VERSION 5.8 ;
BUSBITCHARS "[]" ;
DIVIDERCHAR "/" ;

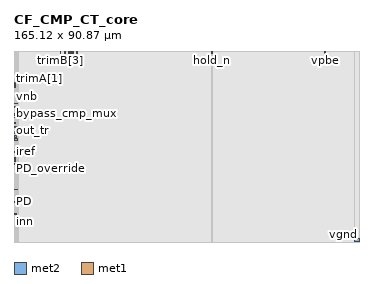
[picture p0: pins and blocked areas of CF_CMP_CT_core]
MACRO CF_CMP_CT_core
  CLASS BLOCK ;
  ORIGIN 0 0 ;
  FOREIGN CF_CMP_CT_core 0 0 ;
  SIZE 165.12 BY 90.87 ;
  PIN trimA[2]
    DIRECTION INPUT ;
    USE SIGNAL ;
    PORT
      LAYER met2 ;
        RECT 0 74.01 0.775 74.33 ;
    END
  END trimA[2]
  PIN trimA[1]
    DIRECTION INPUT ;
    USE SIGNAL ;
    PORT
      LAYER met2 ;
        RECT 0 74.49 0.77 74.81 ;
    END
  END trimA[1]
  PIN bypass_cmp_mux
    DIRECTION INPUT ;
    USE SIGNAL ;
    PORT
      LAYER met2 ;
        RECT 0 61.22 0.645 61.54 ;
    END
  END bypass_cmp_mux
  PIN trimB[4]
    DIRECTION INPUT ;
    USE SIGNAL ;
    PORT
      LAYER met1 ;
        RECT 27.305 90.115 27.625 90.87 ;
    END
  END trimB[4]
  PIN trimB[0]
    DIRECTION INPUT ;
    USE SIGNAL ;
    PORT
      LAYER met1 ;
        RECT 26.58 90.115 26.9 90.87 ;
    END
  END trimB[0]
  PIN trimB[1]
    DIRECTION INPUT ;
    USE SIGNAL ;
    PORT
      LAYER met1 ;
        RECT 26.02 90.175 26.335 90.87 ;
    END
  END trimB[1]
  PIN trimB[2]
    DIRECTION INPUT ;
    USE SIGNAL ;
    PORT
      LAYER met1 ;
        RECT 24.14 90.135 24.46 90.87 ;
    END
  END trimB[2]
  PIN trimB[3]
    DIRECTION INPUT ;
    USE SIGNAL ;
    PORT
      LAYER met1 ;
        RECT 22.135 90.245 22.455 90.87 ;
    END
  END trimB[3]
  PIN trimA[4]
    DIRECTION INPUT ;
    USE SIGNAL ;
    PORT
      LAYER met2 ;
        RECT 0 75.945 0.8 76.265 ;
    END
  END trimA[4]
  PIN trimA[3]
    DIRECTION INPUT ;
    USE SIGNAL ;
    PORT
      LAYER met2 ;
        RECT 0 75.45 0.805 75.77 ;
    END
  END trimA[3]
  PIN inn
    DIRECTION INPUT ;
    USE SIGNAL ;
    PORT
      LAYER met2 ;
        RECT 0 13.205 1.345 13.525 ;
    END
  END inn
  PIN vpb_ka
    DIRECTION INPUT ;
    USE SIGNAL ;
    PORT
      LAYER met2 ;
        RECT 0 48.565 1.555 49.265 ;
    END
  END vpb_ka
  PIN en
    DIRECTION INPUT ;
    USE SIGNAL ;
    PORT
      LAYER met2 ;
        RECT 0 54.985 1.58 55.305 ;
    END
  END en
  PIN iref
    DIRECTION INPUT ;
    USE SIGNAL ;
    PORT
      LAYER met2 ;
        RECT 0 42.935 0.82 43.245 ;
    END
  END iref
  PIN vpwr
    DIRECTION INPUT ;
    USE POWER ;
    PORT
      LAYER met2 ;
        RECT 0 60.32 1.78 61.05 ;
    END
  END vpwr
  PIN vpb
    DIRECTION INPUT ;
    USE POWER ;
    PORT
      LAYER met2 ;
        RECT 0 64.495 0.685 64.815 ;
    END
  END vpb
  PIN vnb
    DIRECTION INPUT ;
    USE GROUND ;
    PORT
      LAYER met2 ;
        RECT 1.71 69.605 2.39 69.925 ;
    END
  END vnb
  PIN vgnd
    DIRECTION INPUT ;
    USE GROUND ;
    PORT
      LAYER met2 ;
        RECT 162.9 0.27 165.06 1.805 ;
    END
  END vgnd
  PIN out
    DIRECTION OUTPUT ;
    USE SIGNAL ;
    PORT
      LAYER met2 ;
        RECT 0 66.085 1.76 66.37 ;
    END
  END out
  PIN out_tr
    DIRECTION OUTPUT ;
    USE SIGNAL ;
    PORT
      LAYER met2 ;
        RECT 0 56.88 0.935 57.2 ;
    END
  END out_tr
  PIN vpwr_ka
    DIRECTION INPUT ;
    USE SIGNAL ;
    PORT
      LAYER met2 ;
        RECT 0 50.005 1.245 50.705 ;
    END
  END vpwr_ka
  PIN cal_en
    DIRECTION INPUT ;
    USE SIGNAL ;
    PORT
      LAYER met2 ;
        RECT 0 59.315 1.465 59.635 ;
    END
  END cal_en
  PIN hyst
    DIRECTION INPUT ;
    USE SIGNAL ;
    PORT
      LAYER met2 ;
        RECT 0 51.74 1.12 52.06 ;
    END
  END hyst
  PIN PD
    DIRECTION INPUT ;
    USE SIGNAL ;
    PORT
      LAYER met2 ;
        RECT 0 19.105 1.02 19.425 ;
    END
  END PD
  PIN filt
    DIRECTION INPUT ;
    USE SIGNAL ;
    PORT
      LAYER met2 ;
        RECT 0 52.33 1.215 52.65 ;
    END
  END filt
  PIN PD_override
    DIRECTION INPUT ;
    USE SIGNAL ;
    PORT
      LAYER met2 ;
        RECT 0 38.685 0.945 39.005 ;
    END
  END PD_override
  PIN hold_n
    DIRECTION INPUT ;
    USE SIGNAL ;
    PORT
      LAYER met2 ;
        RECT 94.55 90.145 94.87 90.87 ;
    END
  END hold_n
  PIN enable_hv
    DIRECTION INPUT ;
    USE SIGNAL ;
    PORT
      LAYER met2 ;
        RECT 0 37.28 0.97 37.595 ;
    END
  END enable_hv
  PIN trimA[0]
    DIRECTION INPUT ;
    USE SIGNAL ;
    PORT
      LAYER met2 ;
        RECT 0 74.97 0.79 75.29 ;
    END
  END trimA[0]
  PIN vpbe
    DIRECTION INPUT ;
    USE POWER ;
    PORT
      LAYER met1 ;
        RECT 148.5 90.13 149.08 90.87 ;
    END
  END vpbe
  PIN vpwre
    DIRECTION INPUT ;
    USE POWER ;
    PORT
      LAYER met1 ;
        RECT 0 39.23 0.94 40.21 ;
    END
  END vpwre
  PIN sel1
    DIRECTION INPUT ;
    USE SIGNAL ;
    PORT
      LAYER met1 ;
        RECT 30.035 90.15 30.355 90.87 ;
    END
  END sel1
  PIN sel0
    DIRECTION INPUT ;
    USE SIGNAL ;
    PORT
      LAYER met1 ;
        RECT 28.15 90.125 28.47 90.87 ;
    END
  END sel0
  PIN inp
    DIRECTION INPUT ;
    USE SIGNAL ;
    PORT
      LAYER met1 ;
        RECT 0 24.89 1.645 25.21 ;
    END
  END inp
  OBS
    LAYER li1 ;
      RECT 0 0 165.12 90.87 ;
    LAYER met1 ;
      RECT 0 0 0.94 24.89 ;
      RECT 0 25.21 0.94 39.23 ;
      RECT 0 40.21 0.94 90.87 ;
      RECT 0.94 0 1.645 24.89 ;
      RECT 0.94 25.21 1.645 90.87 ;
      RECT 1.645 0 22.135 90.87 ;
      RECT 22.135 0 22.455 90.245 ;
      RECT 22.455 0 24.14 90.87 ;
      RECT 24.14 0 24.46 90.135 ;
      RECT 24.46 0 26.02 90.87 ;
      RECT 26.02 0 26.335 90.175 ;
      RECT 26.335 0 26.58 90.87 ;
      RECT 26.58 0 26.9 90.115 ;
      RECT 26.9 0 27.305 90.87 ;
      RECT 27.305 0 27.625 90.115 ;
      RECT 27.625 0 28.15 90.87 ;
      RECT 28.15 0 28.47 90.125 ;
      RECT 28.47 0 30.035 90.87 ;
      RECT 30.035 0 30.355 90.15 ;
      RECT 30.355 0 148.5 90.87 ;
      RECT 148.5 0 149.08 90.13 ;
      RECT 149.08 0 165.12 90.87 ;
    LAYER met2 ;
      RECT 0 0 0.645 13.205 ;
      RECT 0 13.525 0.645 19.105 ;
      RECT 0 19.425 0.645 37.28 ;
      RECT 0 37.595 0.645 38.685 ;
      RECT 0 39.005 0.645 42.935 ;
      RECT 0 43.245 0.645 48.565 ;
      RECT 0 49.265 0.645 50.005 ;
      RECT 0 50.705 0.645 51.74 ;
      RECT 0 52.06 0.645 52.33 ;
      RECT 0 52.65 0.645 54.985 ;
      RECT 0 55.305 0.645 56.88 ;
      RECT 0 57.2 0.645 59.315 ;
      RECT 0 59.635 0.645 60.32 ;
      RECT 0 61.05 0.645 61.22 ;
      RECT 0 61.54 0.645 64.495 ;
      RECT 0 64.815 0.645 66.085 ;
      RECT 0 66.37 0.645 74.01 ;
      RECT 0 74.33 0.645 74.49 ;
      RECT 0 74.81 0.645 74.97 ;
      RECT 0 75.29 0.645 75.45 ;
      RECT 0 75.77 0.645 75.945 ;
      RECT 0 76.265 0.645 90.87 ;
      RECT 0.645 0 0.685 13.205 ;
      RECT 0.645 13.525 0.685 19.105 ;
      RECT 0.645 19.425 0.685 37.28 ;
      RECT 0.645 37.595 0.685 38.685 ;
      RECT 0.645 39.005 0.685 42.935 ;
      RECT 0.645 43.245 0.685 48.565 ;
      RECT 0.645 49.265 0.685 50.005 ;
      RECT 0.645 50.705 0.685 51.74 ;
      RECT 0.645 52.06 0.685 52.33 ;
      RECT 0.645 52.65 0.685 54.985 ;
      RECT 0.645 55.305 0.685 56.88 ;
      RECT 0.645 57.2 0.685 59.315 ;
      RECT 0.645 59.635 0.685 60.32 ;
      RECT 0.645 61.05 0.685 64.495 ;
      RECT 0.645 64.815 0.685 66.085 ;
      RECT 0.645 66.37 0.685 74.01 ;
      RECT 0.645 74.33 0.685 74.49 ;
      RECT 0.645 74.81 0.685 74.97 ;
      RECT 0.645 75.29 0.685 75.45 ;
      RECT 0.645 75.77 0.685 75.945 ;
      RECT 0.645 76.265 0.685 90.87 ;
      RECT 0.685 0 0.77 13.205 ;
      RECT 0.685 13.525 0.77 19.105 ;
      RECT 0.685 19.425 0.77 37.28 ;
      RECT 0.685 37.595 0.77 38.685 ;
      RECT 0.685 39.005 0.77 42.935 ;
      RECT 0.685 43.245 0.77 48.565 ;
      RECT 0.685 49.265 0.77 50.005 ;
      RECT 0.685 50.705 0.77 51.74 ;
      RECT 0.685 52.06 0.77 52.33 ;
      RECT 0.685 52.65 0.77 54.985 ;
      RECT 0.685 55.305 0.77 56.88 ;
      RECT 0.685 57.2 0.77 59.315 ;
      RECT 0.685 59.635 0.77 60.32 ;
      RECT 0.685 61.05 0.77 66.085 ;
      RECT 0.685 66.37 0.77 74.01 ;
      RECT 0.685 74.33 0.77 74.49 ;
      RECT 0.685 74.81 0.77 74.97 ;
      RECT 0.685 75.29 0.77 75.45 ;
      RECT 0.685 75.77 0.77 75.945 ;
      RECT 0.685 76.265 0.77 90.87 ;
      RECT 0.77 0 0.775 13.205 ;
      RECT 0.77 13.525 0.775 19.105 ;
      RECT 0.77 19.425 0.775 37.28 ;
      RECT 0.77 37.595 0.775 38.685 ;
      RECT 0.77 39.005 0.775 42.935 ;
      RECT 0.77 43.245 0.775 48.565 ;
      RECT 0.77 49.265 0.775 50.005 ;
      RECT 0.77 50.705 0.775 51.74 ;
      RECT 0.77 52.06 0.775 52.33 ;
      RECT 0.77 52.65 0.775 54.985 ;
      RECT 0.77 55.305 0.775 56.88 ;
      RECT 0.77 57.2 0.775 59.315 ;
      RECT 0.77 59.635 0.775 60.32 ;
      RECT 0.77 61.05 0.775 66.085 ;
      RECT 0.77 66.37 0.775 74.01 ;
      RECT 0.77 74.33 0.775 74.97 ;
      RECT 0.77 75.29 0.775 75.45 ;
      RECT 0.77 75.77 0.775 75.945 ;
      RECT 0.77 76.265 0.775 90.87 ;
      RECT 0.775 0 0.79 13.205 ;
      RECT 0.775 13.525 0.79 19.105 ;
      RECT 0.775 19.425 0.79 37.28 ;
      RECT 0.775 37.595 0.79 38.685 ;
      RECT 0.775 39.005 0.79 42.935 ;
      RECT 0.775 43.245 0.79 48.565 ;
      RECT 0.775 49.265 0.79 50.005 ;
      RECT 0.775 50.705 0.79 51.74 ;
      RECT 0.775 52.06 0.79 52.33 ;
      RECT 0.775 52.65 0.79 54.985 ;
      RECT 0.775 55.305 0.79 56.88 ;
      RECT 0.775 57.2 0.79 59.315 ;
      RECT 0.775 59.635 0.79 60.32 ;
      RECT 0.775 61.05 0.79 66.085 ;
      RECT 0.775 66.37 0.79 74.97 ;
      RECT 0.775 75.29 0.79 75.45 ;
      RECT 0.775 75.77 0.79 75.945 ;
      RECT 0.775 76.265 0.79 90.87 ;
      RECT 0.79 0 0.8 13.205 ;
      RECT 0.79 13.525 0.8 19.105 ;
      RECT 0.79 19.425 0.8 37.28 ;
      RECT 0.79 37.595 0.8 38.685 ;
      RECT 0.79 39.005 0.8 42.935 ;
      RECT 0.79 43.245 0.8 48.565 ;
      RECT 0.79 49.265 0.8 50.005 ;
      RECT 0.79 50.705 0.8 51.74 ;
      RECT 0.79 52.06 0.8 52.33 ;
      RECT 0.79 52.65 0.8 54.985 ;
      RECT 0.79 55.305 0.8 56.88 ;
      RECT 0.79 57.2 0.8 59.315 ;
      RECT 0.79 59.635 0.8 60.32 ;
      RECT 0.79 61.05 0.8 66.085 ;
      RECT 0.79 66.37 0.8 75.45 ;
      RECT 0.79 75.77 0.8 75.945 ;
      RECT 0.79 76.265 0.8 90.87 ;
      RECT 0.8 0 0.805 13.205 ;
      RECT 0.8 13.525 0.805 19.105 ;
      RECT 0.8 19.425 0.805 37.28 ;
      RECT 0.8 37.595 0.805 38.685 ;
      RECT 0.8 39.005 0.805 42.935 ;
      RECT 0.8 43.245 0.805 48.565 ;
      RECT 0.8 49.265 0.805 50.005 ;
      RECT 0.8 50.705 0.805 51.74 ;
      RECT 0.8 52.06 0.805 52.33 ;
      RECT 0.8 52.65 0.805 54.985 ;
      RECT 0.8 55.305 0.805 56.88 ;
      RECT 0.8 57.2 0.805 59.315 ;
      RECT 0.8 59.635 0.805 60.32 ;
      RECT 0.8 61.05 0.805 66.085 ;
      RECT 0.8 66.37 0.805 75.45 ;
      RECT 0.8 75.77 0.805 90.87 ;
      RECT 0.805 0 0.82 13.205 ;
      RECT 0.805 13.525 0.82 19.105 ;
      RECT 0.805 19.425 0.82 37.28 ;
      RECT 0.805 37.595 0.82 38.685 ;
      RECT 0.805 39.005 0.82 42.935 ;
      RECT 0.805 43.245 0.82 48.565 ;
      RECT 0.805 49.265 0.82 50.005 ;
      RECT 0.805 50.705 0.82 51.74 ;
      RECT 0.805 52.06 0.82 52.33 ;
      RECT 0.805 52.65 0.82 54.985 ;
      RECT 0.805 55.305 0.82 56.88 ;
      RECT 0.805 57.2 0.82 59.315 ;
      RECT 0.805 59.635 0.82 60.32 ;
      RECT 0.805 61.05 0.82 66.085 ;
      RECT 0.805 66.37 0.82 90.87 ;
      RECT 0.82 0 0.935 13.205 ;
      RECT 0.82 13.525 0.935 19.105 ;
      RECT 0.82 19.425 0.935 37.28 ;
      RECT 0.82 37.595 0.935 38.685 ;
      RECT 0.82 39.005 0.935 48.565 ;
      RECT 0.82 49.265 0.935 50.005 ;
      RECT 0.82 50.705 0.935 51.74 ;
      RECT 0.82 52.06 0.935 52.33 ;
      RECT 0.82 52.65 0.935 54.985 ;
      RECT 0.82 55.305 0.935 56.88 ;
      RECT 0.82 57.2 0.935 59.315 ;
      RECT 0.82 59.635 0.935 60.32 ;
      RECT 0.82 61.05 0.935 66.085 ;
      RECT 0.82 66.37 0.935 90.87 ;
      RECT 0.935 0 0.945 13.205 ;
      RECT 0.935 13.525 0.945 19.105 ;
      RECT 0.935 19.425 0.945 37.28 ;
      RECT 0.935 37.595 0.945 38.685 ;
      RECT 0.935 39.005 0.945 48.565 ;
      RECT 0.935 49.265 0.945 50.005 ;
      RECT 0.935 50.705 0.945 51.74 ;
      RECT 0.935 52.06 0.945 52.33 ;
      RECT 0.935 52.65 0.945 54.985 ;
      RECT 0.935 55.305 0.945 59.315 ;
      RECT 0.935 59.635 0.945 60.32 ;
      RECT 0.935 61.05 0.945 66.085 ;
      RECT 0.935 66.37 0.945 90.87 ;
      RECT 0.945 0 0.97 13.205 ;
      RECT 0.945 13.525 0.97 19.105 ;
      RECT 0.945 19.425 0.97 37.28 ;
      RECT 0.945 37.595 0.97 48.565 ;
      RECT 0.945 49.265 0.97 50.005 ;
      RECT 0.945 50.705 0.97 51.74 ;
      RECT 0.945 52.06 0.97 52.33 ;
      RECT 0.945 52.65 0.97 54.985 ;
      RECT 0.945 55.305 0.97 59.315 ;
      RECT 0.945 59.635 0.97 60.32 ;
      RECT 0.945 61.05 0.97 66.085 ;
      RECT 0.945 66.37 0.97 90.87 ;
      RECT 0.97 0 1.02 13.205 ;
      RECT 0.97 13.525 1.02 19.105 ;
      RECT 0.97 19.425 1.02 48.565 ;
      RECT 0.97 49.265 1.02 50.005 ;
      RECT 0.97 50.705 1.02 51.74 ;
      RECT 0.97 52.06 1.02 52.33 ;
      RECT 0.97 52.65 1.02 54.985 ;
      RECT 0.97 55.305 1.02 59.315 ;
      RECT 0.97 59.635 1.02 60.32 ;
      RECT 0.97 61.05 1.02 66.085 ;
      RECT 0.97 66.37 1.02 90.87 ;
      RECT 1.02 0 1.12 13.205 ;
      RECT 1.02 13.525 1.12 48.565 ;
      RECT 1.02 49.265 1.12 50.005 ;
      RECT 1.02 50.705 1.12 51.74 ;
      RECT 1.02 52.06 1.12 52.33 ;
      RECT 1.02 52.65 1.12 54.985 ;
      RECT 1.02 55.305 1.12 59.315 ;
      RECT 1.02 59.635 1.12 60.32 ;
      RECT 1.02 61.05 1.12 66.085 ;
      RECT 1.02 66.37 1.12 90.87 ;
      RECT 1.12 0 1.215 13.205 ;
      RECT 1.12 13.525 1.215 48.565 ;
      RECT 1.12 49.265 1.215 50.005 ;
      RECT 1.12 50.705 1.215 52.33 ;
      RECT 1.12 52.65 1.215 54.985 ;
      RECT 1.12 55.305 1.215 59.315 ;
      RECT 1.12 59.635 1.215 60.32 ;
      RECT 1.12 61.05 1.215 66.085 ;
      RECT 1.12 66.37 1.215 90.87 ;
      RECT 1.215 0 1.245 13.205 ;
      RECT 1.215 13.525 1.245 48.565 ;
      RECT 1.215 49.265 1.245 50.005 ;
      RECT 1.215 50.705 1.245 54.985 ;
      RECT 1.215 55.305 1.245 59.315 ;
      RECT 1.215 59.635 1.245 60.32 ;
      RECT 1.215 61.05 1.245 66.085 ;
      RECT 1.215 66.37 1.245 90.87 ;
      RECT 1.245 0 1.345 13.205 ;
      RECT 1.245 13.525 1.345 48.565 ;
      RECT 1.245 49.265 1.345 54.985 ;
      RECT 1.245 55.305 1.345 59.315 ;
      RECT 1.245 59.635 1.345 60.32 ;
      RECT 1.245 61.05 1.345 66.085 ;
      RECT 1.245 66.37 1.345 90.87 ;
      RECT 1.345 0 1.465 48.565 ;
      RECT 1.345 49.265 1.465 54.985 ;
      RECT 1.345 55.305 1.465 59.315 ;
      RECT 1.345 59.635 1.465 60.32 ;
      RECT 1.345 61.05 1.465 66.085 ;
      RECT 1.345 66.37 1.465 90.87 ;
      RECT 1.465 0 1.555 48.565 ;
      RECT 1.465 49.265 1.555 54.985 ;
      RECT 1.465 55.305 1.555 60.32 ;
      RECT 1.465 61.05 1.555 66.085 ;
      RECT 1.465 66.37 1.555 90.87 ;
      RECT 1.555 0 1.58 54.985 ;
      RECT 1.555 55.305 1.58 60.32 ;
      RECT 1.555 61.05 1.58 66.085 ;
      RECT 1.555 66.37 1.58 90.87 ;
      RECT 1.58 0 1.71 60.32 ;
      RECT 1.58 61.05 1.71 66.085 ;
      RECT 1.58 66.37 1.71 90.87 ;
      RECT 1.71 0 1.76 60.32 ;
      RECT 1.71 61.05 1.76 66.085 ;
      RECT 1.71 66.37 1.76 69.605 ;
      RECT 1.71 69.925 1.76 90.87 ;
      RECT 1.76 0 1.78 60.32 ;
      RECT 1.76 61.05 1.78 69.605 ;
      RECT 1.76 69.925 1.78 90.87 ;
      RECT 1.78 0 2.39 69.605 ;
      RECT 1.78 69.925 2.39 90.87 ;
      RECT 2.39 0 94.55 90.87 ;
      RECT 94.55 0 94.87 90.145 ;
      RECT 94.87 0 162.9 90.87 ;
      RECT 162.9 0 165.06 0.27 ;
      RECT 162.9 1.805 165.06 90.87 ;
      RECT 165.06 0 165.12 90.87 ;
  END
END CF_CMP_CT_core

END LIBRARY
